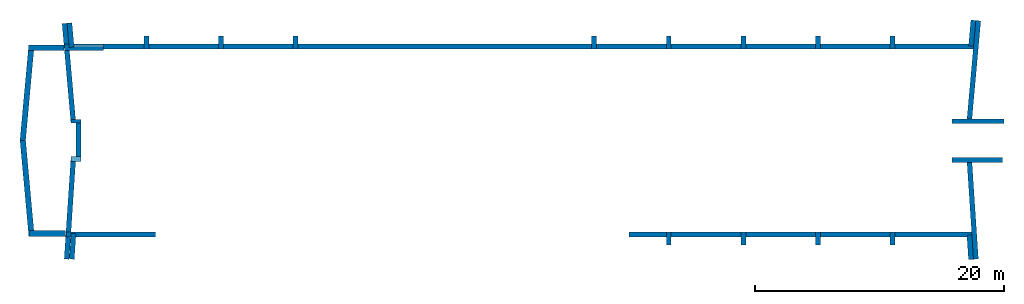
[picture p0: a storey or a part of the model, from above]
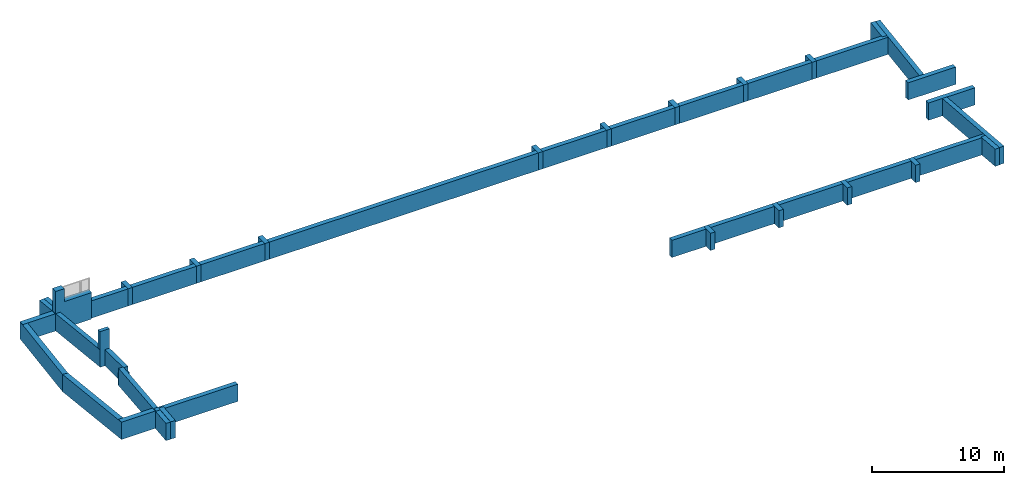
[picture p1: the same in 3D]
Properties of the parts of a building model (IFC2X3)

# File
Description: ViewDefinition [CoordinationView_V2.0], Option [Drawing Scale: 100.000000], Option [Global Unique Identifiers (GUID): Keep existing], Option [Elements to export: Visible elements (on all stories)], Option [Partial Structure Display: Entire Model], Option [IFC Domain: All], Option [Structural Function: All Elements], Option [Convert Grid elements: On], Option [Convert IFC Annotations and ArchiCAD 2D elements: Off], Option [Convert 2D symbols of Doors and Windows: Off], Option [Explode Composite and Complex Profile elements into parts: Off], Option [Export geometries that Participates in Collision Detection only: On], Option [Multi-skin complex geometries: Building element parts], Option [Elements in Solid Element Operations: Extruded/revolved], Option [Elements with junctions: Extruded/revolved without junctions], Option [Slabs with slanted edge(s): Extruded], Option [Use legacy geometric methods as in Coordination View 1.0: Off], Option [IFC Site Geometry: As boundary representation (BRep)], Option [Properties To Export: All properties], Option [Space containment: Off], Option [Bounding Box: Off], Option [Geometry to type objects: Off], Option [IFC base quantities (size, area and volume): Off], Option [All ArchiCAD BIM parameters: Off], Option [IFC Space boundaries: Off], Option [ArchiCAD Zone Categories as IFC Space classification data: Off]
File name: E:\My Documents\AAJOO2108\LasnamĆ¤e mehaanikakool\UUS PROJEKT\TĆ–Ć–\TLMK AR PP TP, SA koos\MUDEL\AR_TLMK_PP_15.02.19.ifc
Time: 2019-02-15T14:08:49
Author: Architect
Organization: Building Designer Office
Written by: PreProc - EDM 5.0
Made in: IFC file generated by Graphisoft ArchiCAD-64 19.0.0 INT FULL Windows version (IFC2x3 add-on version: 3003 INT FULL).
Authorization: The authorising person

# IfcSite, Site
RefLatitude: 24, 28, 0, 0; RefLongitude: 54, 25, 0, 0; RefElevation: 0 mm

# IfcBuildingStorey (6)
In: Building
Name | Elevation (mm)
Sokkel | -5000
1KORRUS | -3400
2KORRUS | 0
3KORRUS | 3200
4KORRUS | 6300
5KORRUS | 9500

# IfcSpace: Office (261)
InteriorOrExteriorSpace: INTERNAL
Pset_SpaceCommon - Category: Office
AC_Pset_RenovationAndPhasing - Renovation Status: Existing
Name | In
104 | 1KORRUS
101 | 1KORRUS | LongName: FUAJEE
105 | 1KORRUS
103 | 1KORRUS
102 | 1KORRUS | LongName: VALVE
333 | 3KORRUS
366 | 3KORRUS
341 | 3KORRUS
358 | 3KORRUS
306 | 3KORRUS
337 | 3KORRUS
334 | 3KORRUS
343 | 3KORRUS
347 | 3KORRUS
375 | 3KORRUS
317 | 3KORRUS
380 | 3KORRUS
335 | 3KORRUS
383 | 3KORRUS
303 | 3KORRUS
331 | 3KORRUS
305a | 3KORRUS
336 | 3KORRUS
338 | 3KORRUS
339 | 3KORRUS
340 | 3KORRUS
308 | 3KORRUS
362 | 3KORRUS
361 | 3KORRUS
369 | 3KORRUS
332 | 3KORRUS
368 | 3KORRUS
355 | 3KORRUS
357 | 3KORRUS
356 | 3KORRUS
354 | 3KORRUS
360 | 3KORRUS
363 | 3KORRUS
364 | 3KORRUS
365 | 3KORRUS
382 | 3KORRUS
378 | 3KORRUS
381 | 3KORRUS
350 | 3KORRUS
379 | 3KORRUS
349 | 3KORRUS
353 | 3KORRUS
352 | 3KORRUS
351 | 3KORRUS
376 | 3KORRUS
348 | 3KORRUS
373 | 3KORRUS
374 | 3KORRUS
372 | 3KORRUS
316 | 3KORRUS
311 | 3KORRUS
310 | 3KORRUS
309 | 3KORRUS
305 | 3KORRUS
377 | 3KORRUS
370 | 3KORRUS
371 | 3KORRUS
359 | 3KORRUS
325 | 3KORRUS
330 | 3KORRUS
328 | 3KORRUS
329 | 3KORRUS
326 | 3KORRUS
315 | 3KORRUS
314 | 3KORRUS
313 | 3KORRUS
312 | 3KORRUS
307 | 3KORRUS
302 | 3KORRUS
304 | 3KORRUS
301 | 3KORRUS
344 | 3KORRUS
342 | 3KORRUS
346 | 3KORRUS
345 | 3KORRUS
319 | 3KORRUS
318 | 3KORRUS
323 | 3KORRUS
322 | 3KORRUS
321 | 3KORRUS
320 | 3KORRUS
324 | 3KORRUS
318a | 3KORRUS
424 | 4KORRUS
402 | 4KORRUS
460 | 4KORRUS
467 | 4KORRUS
2 x 459 | 4KORRUS
415 | 4KORRUS
465 | 4KORRUS
418 | 4KORRUS
426 | 4KORRUS
471 | 4KORRUS
309 | 4KORRUS
474 | 4KORRUS
478 | 4KORRUS
439 | 4KORRUS
455 | 4KORRUS
2 x 433 | 4KORRUS
464 | 4KORRUS
420 | 4KORRUS
457 | 4KORRUS
418a | 4KORRUS
438 | 4KORRUS
440 | 4KORRUS
437 | 4KORRUS
412 | 4KORRUS
414 | 4KORRUS
425 | 4KORRUS
405 | 4KORRUS
404 | 4KORRUS
427 | 4KORRUS
422 | 4KORRUS
410 | 4KORRUS
411 | 4KORRUS
458 | 4KORRUS
423 | 4KORRUS
486 | 4KORRUS
485 | 4KORRUS
484 | 4KORRUS
487 | 4KORRUS
450 | 4KORRUS
401 | 4KORRUS
444 | 4KORRUS
462 | 4KORRUS
483 | 4KORRUS
482 | 4KORRUS
472 | 4KORRUS
406 | 4KORRUS
466 | 4KORRUS
481 | 4KORRUS
463 | 4KORRUS
479 | 4KORRUS
476 | 4KORRUS
416 | 4KORRUS
317 | 4KORRUS
477 | 4KORRUS
429 | 4KORRUS
430 | 4KORRUS
469 | 4KORRUS
470 | 4KORRUS
473 | 4KORRUS
419 | 4KORRUS
413 | 4KORRUS
431 | 4KORRUS
448 | 4KORRUS
447 | 4KORRUS
454 | 4KORRUS
428 | 4KORRUS
432 | 4KORRUS
435 | 4KORRUS
434 | 4KORRUS
436 | 4KORRUS
441 | 4KORRUS
443 | 4KORRUS
453 | 4KORRUS
452 | 4KORRUS
445 | 4KORRUS
446 | 4KORRUS
451 | 4KORRUS
456 | 4KORRUS
407 | 4KORRUS
403 | 4KORRUS
421 | 4KORRUS
480 | 4KORRUS
408 | 4KORRUS
402a | 4KORRUS
525 | 5KORRUS
526 | 5KORRUS
552 | 5KORRUS
564 | 5KORRUS
543 | 5KORRUS
544 | 5KORRUS
541 | 5KORRUS
563 | 5KORRUS
530 | 5KORRUS
558 | 5KORRUS
584 | 5KORRUS
582 | 5KORRUS
532 | 5KORRUS
583 | 5KORRUS
562 | 5KORRUS
570 | 5KORRUS
560 | 5KORRUS
540 | 5KORRUS
561 | 5KORRUS
535 | 5KORRUS
539 | 5KORRUS
529 | 5KORRUS
545 | 5KORRUS
542 | 5KORRUS
549 | 5KORRUS
556 | 5KORRUS
559 | 5KORRUS
533 | 5KORRUS
551 | 5KORRUS
527 | 5KORRUS
528 | 5KORRUS
524 | 5KORRUS
511 | 5KORRUS
509 | 5KORRUS
508 | 5KORRUS
573 | 5KORRUS
575 | 5KORRUS
550 | 5KORRUS
574 | 5KORRUS
569 | 5KORRUS
548 | 5KORRUS
571 | 5KORRUS
572 | 5KORRUS
555 | 5KORRUS
557 | 5KORRUS
534 | 5KORRUS
536 | 5KORRUS
546 | 5KORRUS
538 | 5KORRUS
537 | 5KORRUS
547 | 5KORRUS
531 | 5KORRUS
502a | 5KORRUS
504 | 5KORRUS
503 | 5KORRUS
512 | 5KORRUS
513 | 5KORRUS
510 | 5KORRUS
553 | 5KORRUS
554 | 5KORRUS
501 | 5KORRUS
585 | 5KORRUS
581 | 5KORRUS
502 | 5KORRUS
576 | 5KORRUS
577 | 5KORRUS
578 | 5KORRUS
567 | 5KORRUS
565 | 5KORRUS
568 | 5KORRUS
566 | 5KORRUS
580 | 5KORRUS
579 | 5KORRUS
505 | 5KORRUS
506 | 5KORRUS
507 | 5KORRUS
514 | 5KORRUS
515 | 5KORRUS
516 | 5KORRUS
517 | 5KORRUS
518 | 5KORRUS
2 x 518a | 5KORRUS
520 | 5KORRUS
521 | 5KORRUS
522 | 5KORRUS
523 | 5KORRUS

# IfcBuildingElementProxy: Vertical Ladder 19, R1
In: 5KORRUS
Description: REDEL; Material: Background
AC_Pset_RenovationAndPhasing - Renovation Status: Existing

# IfcBuildingElementProxy: Wheelchair Man Symbol 19 (4)
In: 3KORRUS
Material: Background
AC_Pset_RenovationAndPhasing - Renovation Status: Existing

# IfcCovering: Alumiiniumprofiil 50 (61)
Description: Ripplagi; PredefinedType: CEILING; Material: Alumiiniumprofiil
Pset_CoveringCommon - Material: Alumiiniumprofiil
AC_Pset_RenovationAndPhasing - Renovation Status: Existing
Name | In
RL2 | 1KORRUS
18 x RL2 | 3KORRUS
RL3 | 3KORRUS
21 x RL2 | 4KORRUS
19 x RL2 | 5KORRUS
RL3 | 5KORRUS

# IfcCovering: Betoon 50 (5)
Description: Ripplagi; PredefinedType: CEILING; Material: Betoon
Pset_CoveringCommon - Material: Betoon
AC_Pset_RenovationAndPhasing - Renovation Status: Existing
Name | In
3 x RL1 | 1KORRUS
2 x RL2 | 5KORRUS

# IfcCovering: Terasvõrk 50 (9)
Description: Ripplagi; PredefinedType: CEILING; Material: Terasvõrk
Pset_CoveringCommon - Material: Terasvõrk
AC_Pset_RenovationAndPhasing - Renovation Status: Existing
Name | In
RL1 | 3KORRUS
2 x RL3 | 3KORRUS
RL1 | 4KORRUS
2 x RL3 | 4KORRUS
2 x RL3 | 5KORRUS
RL1 | 5KORRUS

# IfcCovering: UmbKipsplaat 50 (75)
Description: Ripplagi; PredefinedType: CEILING; Material: UmbKipsplaat
Pset_CoveringCommon - Material: UmbKipsplaat
AC_Pset_RenovationAndPhasing - Renovation Status: Existing
Name | In
RL7 | 3KORRUS
24 x RL1 | 3KORRUS
25 x RL1 | 4KORRUS
25 x RL1 | 5KORRUS

# IfcCovering: Window 19 (3)
Description: VENT.REST; Material: Background
Pset_CoveringCommon - Material: Background
AC_Pset_RenovationAndPhasing - Renovation Status: New
Name | In
VR1 | 3KORRUS
VR1 | 4KORRUS
VR1 | 5KORRUS

# IfcDoor: Door 19 (3)
Type - OperationType: SINGLE_SWING_LEFT; ParameterTakesPrecedence: no; Sizeable: no
Type - Door Lining Properties - LiningDepth: 115 mm; LiningThickness: 40 mm; LiningOffset: -185 mm
Type - Door Panel Properties - Panel 1 - PanelDepth: 40 mm; PanelOperation: SWINGING; PanelWidth: 1; PanelPosition: MIDDLE
Description: Tamme spoon, must peits; OverallHeight: 2100 mm; OverallWidth: 900 mm; Material: Background
AC_Pset_RenovationAndPhasing - Renovation Status: New
Name | In
SU2-6 | 3KORRUS
SU2-6 | 4KORRUS
SU2-6 | 5KORRUS

# IfcDoor: Door 19, SU2-6
In: 3KORRUS
Type - OperationType: SINGLE_SWING_LEFT; ParameterTakesPrecedence: no; Sizeable: no
Type - Door Lining Properties - LiningDepth: 115 mm; LiningThickness: 40 mm; LiningOffset: -3.33067e-13 mm
Type - Door Panel Properties - Panel 1 - PanelDepth: 40 mm; PanelOperation: SWINGING; PanelWidth: 1; PanelPosition: MIDDLE
Description: Tamme spoon, must peits; OverallHeight: 2100 mm; OverallWidth: 900 mm; Material: Background
AC_Pset_RenovationAndPhasing - Renovation Status: New

# IfcDoor: Door 19 (40)
Type - OperationType: SINGLE_SWING_LEFT; ParameterTakesPrecedence: no; Sizeable: no
Type - Door Lining Properties - LiningDepth: 115 mm; LiningThickness: 40 mm; LiningOffset: -35 mm
Type - Door Panel Properties - Panel 1 - PanelDepth: 40 mm; PanelOperation: SWINGING; PanelWidth: 1; PanelPosition: MIDDLE
OverallHeight: 2100 mm; Material: Background
AC_Pset_RenovationAndPhasing - Renovation Status: New
Name | In | Description | OverallWidth (mm)
7 x SU3-5 | 3KORRUS | RAL9016 | 800
SU2-6 | 3KORRUS | Tamme spoon, must peits | 900
SU2-3 | 3KORRUS | Tamme spoon, must peits | 900
9 x SU3-5 | 4KORRUS | RAL9016 | 800
SU2-3 | 4KORRUS | Tamme spoon, must peits | 900
SU2-4 | 4KORRUS | Tamme spoon, must peits | 900
14 x SU3-5 | 5KORRUS | RAL9016 | 800
2 x SU2-3 | 5KORRUS | Tamme spoon, must peits | 900
SU2-4 | 5KORRUS | Tamme spoon, must peits | 900
3 x SU2-6 | 5KORRUS | Tamme spoon, must peits | 900

# IfcDoor: Door 19 (2)
Type - OperationType: SINGLE_SWING_LEFT; ParameterTakesPrecedence: no; Sizeable: no
Type - Door Lining Properties - LiningDepth: 115 mm; LiningThickness: 40 mm; LiningOffset: -7.21645e-13 mm
Type - Door Panel Properties - Panel 1 - PanelDepth: 40 mm; PanelOperation: SWINGING; PanelWidth: 1; PanelPosition: MIDDLE
Description: Tamme spoon, must peits; OverallHeight: 2100 mm; OverallWidth: 900 mm; Material: Background
AC_Pset_RenovationAndPhasing - Renovation Status: New
Name | In
SU2-6 | 4KORRUS
SU2-6 | 5KORRUS

# IfcDoor: Door 19 (82)
Type - OperationType: SINGLE_SWING_LEFT; ParameterTakesPrecedence: no; Sizeable: no
Type - Door Lining Properties - LiningDepth: 115 mm; LiningThickness: 40 mm; LiningOffset: 0 mm
Type - Door Panel Properties - Panel 1 - PanelDepth: 40 mm; PanelOperation: SWINGING; PanelWidth: 1; PanelPosition: MIDDLE
OverallHeight: 2100 mm; Material: Background
AC_Pset_RenovationAndPhasing - Renovation Status: New
Name | In | Description | OverallWidth (mm)
12 x SU3-3 | 3KORRUS | RAL9016 | 800
11 x SU2-6 | 3KORRUS | Tamme spoon, must peits | 900
2 x SU2-4 | 3KORRUS | Tamme spoon, must peits | 900
SU1-4 | 3KORRUS | RAL9016 | 1000
SU1-3 | 3KORRUS | Tamme spoon, must peits | 1000
2 x SU2-4 | 4KORRUS | Tamme spoon, must peits | 900
13 x SU3-3 | 4KORRUS | RAL9016 | 800
13 x SU2-6 | 4KORRUS | Tamme spoon, must peits | 900
SU3-5 | 4KORRUS | RAL9016 | 800
2 x SU3-5 | 5KORRUS | RAL9016 | 800
12 x SU3-3 | 5KORRUS | RAL9016 | 800
10 x SU2-6 | 5KORRUS | Tamme spoon, must peits | 900
2 x SU2-4 | 5KORRUS | Tamme spoon, must peits | 900

# IfcDoor: Door 19 (2)
In: 1KORRUS
Type - OperationType: SINGLE_SWING_LEFT; ParameterTakesPrecedence: no; Sizeable: no
Type - Door Lining Properties - LiningDepth: 115 mm; LiningThickness: 40 mm; LiningOffset: 200 mm
Type - Door Panel Properties - Panel 1 - PanelDepth: 40 mm; PanelOperation: SWINGING; PanelWidth: 1; PanelPosition: MIDDLE
OverallHeight: 2100 mm; OverallWidth: 1000 mm; Material: Background
AC_Pset_RenovationAndPhasing - Renovation Status: Existing

# IfcDoor: Door 19 (16)
Type - OperationType: SINGLE_SWING_LEFT; ParameterTakesPrecedence: no; Sizeable: no
Type - Door Lining Properties - LiningDepth: 115 mm; LiningThickness: 40 mm; LiningOffset: 265 mm
Type - Door Panel Properties - Panel 1 - PanelDepth: 40 mm; PanelOperation: SWINGING; PanelWidth: 1; PanelPosition: MIDDLE
Description: RAL9016; OverallHeight: 2100 mm; OverallWidth: 800 mm; Material: Background
AC_Pset_RenovationAndPhasing - Renovation Status: New
Name | In
5 x SU3-5 | 3KORRUS
SU3-1 | 3KORRUS
6 x SU3-5 | 4KORRUS
4 x SU3-5 | 5KORRUS

# IfcDoor: Door 19 (3)
Type - OperationType: SINGLE_SWING_LEFT; ParameterTakesPrecedence: no; Sizeable: no
Type - Door Lining Properties - LiningDepth: 115 mm; LiningThickness: 40 mm; LiningOffset: 300 mm
Type - Door Panel Properties - Panel 1 - PanelDepth: 40 mm; PanelOperation: SWINGING; PanelWidth: 1; PanelPosition: MIDDLE
OverallHeight: 2100 mm; Material: Background
AC_Pset_RenovationAndPhasing - Renovation Status: New
Name | In | Description | OverallWidth (mm)
SU3-1 | 3KORRUS | RAL9016 | 800
SU2-6 | 4KORRUS | Tamme spoon, must peits | 900
SU2-6 | 5KORRUS | Tamme spoon, must peits | 900

# IfcDoor: Door 19 (2)
In: 1KORRUS
Type - OperationType: SINGLE_SWING_LEFT; ParameterTakesPrecedence: no; Sizeable: no
Type - Door Lining Properties - LiningDepth: 115 mm; LiningThickness: 40 mm; LiningOffset: 600 mm
Type - Door Panel Properties - Panel 1 - PanelDepth: 40 mm; PanelOperation: SWINGING; PanelWidth: 1; PanelPosition: MIDDLE
OverallHeight: 2100 mm; OverallWidth: 1000 mm; Material: Background
AC_Pset_RenovationAndPhasing - Renovation Status: Existing

# IfcDoor: Door 19 (14)
Type - OperationType: SINGLE_SWING_RIGHT; ParameterTakesPrecedence: no; Sizeable: no
Type - Door Lining Properties - LiningDepth: 115 mm; LiningThickness: 40 mm; LiningOffset: -3.33067e-13 mm
Type - Door Panel Properties - Panel 1 - PanelDepth: 40 mm; PanelOperation: SWINGING; PanelWidth: 1; PanelPosition: MIDDLE
OverallHeight: 2100 mm; Material: Background
AC_Pset_RenovationAndPhasing - Renovation Status: New
Name | In | Description | OverallWidth (mm)
2 x SU2-5 | 3KORRUS | Tamme spoon, must peits | 900
SU2-1 | 3KORRUS | Tamme spoon, must peits | 900
SU1-1 | 3KORRUS | Tamme spoon, must peits | 1000
SU1-2 | 3KORRUS | RAL9016 | 1000
3 x SU2-5 | 4KORRUS | Tamme spoon, must peits | 900
SU3-2 | 4KORRUS | RAL9016 | 800
2 x SU3-2 | 5KORRUS | RAL9016 | 800
3 x SU2-5 | 5KORRUS | Tamme spoon, must peits | 900

# IfcDoor: Door 19 (25)
Type - OperationType: SINGLE_SWING_RIGHT; ParameterTakesPrecedence: no; Sizeable: no
Type - Door Lining Properties - LiningDepth: 115 mm; LiningThickness: 40 mm; LiningOffset: -35 mm
Type - Door Panel Properties - Panel 1 - PanelDepth: 40 mm; PanelOperation: SWINGING; PanelWidth: 1; PanelPosition: MIDDLE
OverallHeight: 2100 mm; Material: Background
AC_Pset_RenovationAndPhasing - Renovation Status: New
Name | In | Description | OverallWidth (mm)
7 x SU3-4 | 3KORRUS | RAL9016 | 800
SU2-1 | 4KORRUS | Tamme spoon, must peits | 900
9 x SU3-4 | 4KORRUS | RAL9016 | 800
8 x SU3-4 | 5KORRUS | RAL9016 | 800

# IfcDoor: Door 19 (5)
Type - OperationType: SINGLE_SWING_RIGHT; ParameterTakesPrecedence: no; Sizeable: no
Type - Door Lining Properties - LiningDepth: 115 mm; LiningThickness: 40 mm; LiningOffset: 0 mm; CasingThickness: 50 mm; CasingDepth: 19 mm
Type - Door Panel Properties - Panel 1 - PanelDepth: 40 mm; PanelOperation: SWINGING; PanelWidth: 1; PanelPosition: MIDDLE
Description: metall, klaas; OverallHeight: 2100 mm; OverallWidth: 900 mm; Material: Background
AC_Pset_RenovationAndPhasing - Renovation Status: New
Name | In
Liftiuks | 1KORRUS
Liftiuks | 2KORRUS
Liftiuks | 3KORRUS
Liftiuks | 4KORRUS
Liftiuks | 5KORRUS

# IfcDoor: Door 19 (13)
Type - OperationType: SINGLE_SWING_RIGHT; ParameterTakesPrecedence: no; Sizeable: no
Type - Door Lining Properties - LiningDepth: 115 mm; LiningThickness: 40 mm; LiningOffset: 0 mm
Type - Door Panel Properties - Panel 1 - PanelDepth: 40 mm; PanelOperation: SWINGING; PanelWidth: 1; PanelPosition: MIDDLE
OverallHeight: 2100 mm; Material: Background
AC_Pset_RenovationAndPhasing - Renovation Status: New
Name | In | Description | OverallWidth (mm)
SU3-2 | 1KORRUS | RAL9016 | 800
2 x SU2-2 | 3KORRUS | RAL9016 | 900
2 x SU2-5 | 3KORRUS | Tamme spoon, must peits | 900
SU3-4 | 3KORRUS | RAL9016 | 800
SU3-4 | 4KORRUS | RAL9016 | 800
SU2-5 | 4KORRUS | Tamme spoon, must peits | 900
SU2-2 | 4KORRUS | RAL9016 | 900
SU2-5 | 5KORRUS | Tamme spoon, must peits | 900
2 x SU3-4 | 5KORRUS | RAL9016 | 800
SU2-2 | 5KORRUS | RAL9016 | 900

# IfcDoor: Door 19 (14)
Type - OperationType: SINGLE_SWING_RIGHT; ParameterTakesPrecedence: no; Sizeable: no
Type - Door Lining Properties - LiningDepth: 115 mm; LiningThickness: 40 mm; LiningOffset: 1.44329e-12 mm
Type - Door Panel Properties - Panel 1 - PanelDepth: 40 mm; PanelOperation: SWINGING; PanelWidth: 1; PanelPosition: MIDDLE
Description: RAL9016; OverallHeight: 2100 mm; OverallWidth: 800 mm; Material: Background
AC_Pset_RenovationAndPhasing - Renovation Status: New
Name | In
5 x SU3-2 | 3KORRUS
5 x SU3-2 | 4KORRUS
4 x SU3-2 | 5KORRUS

# IfcDoor: Door 19 (2)
In: 1KORRUS
Type - OperationType: SINGLE_SWING_RIGHT; ParameterTakesPrecedence: no; Sizeable: no
Type - Door Lining Properties - LiningDepth: 115 mm; LiningThickness: 40 mm; LiningOffset: 200 mm
Type - Door Panel Properties - Panel 1 - PanelDepth: 40 mm; PanelOperation: SWINGING; PanelWidth: 1; PanelPosition: MIDDLE
OverallHeight: 2100 mm; OverallWidth: 1000 mm; Material: Background
AC_Pset_RenovationAndPhasing - Renovation Status: Existing

# IfcDoor: Door 19 (23)
Type - OperationType: SINGLE_SWING_RIGHT; ParameterTakesPrecedence: no; Sizeable: no
Type - Door Lining Properties - LiningDepth: 115 mm; LiningThickness: 40 mm; LiningOffset: 265 mm
Type - Door Panel Properties - Panel 1 - PanelDepth: 40 mm; PanelOperation: SWINGING; PanelWidth: 1; PanelPosition: MIDDLE
Description: RAL9016; OverallHeight: 2100 mm; OverallWidth: 800 mm; Material: Background
AC_Pset_RenovationAndPhasing - Renovation Status: New
Name | In
7 x SU3-4 | 3KORRUS
SU3-5 | 3KORRUS
8 x SU3-4 | 4KORRUS
SU3-5 | 4KORRUS
4 x SU3-4 | 5KORRUS
SU3-2 | 5KORRUS
SU3-5 | 5KORRUS

# IfcDoor: Door 19 (2)
Type - OperationType: SINGLE_SWING_RIGHT; ParameterTakesPrecedence: no; Sizeable: no
Type - Door Lining Properties - LiningDepth: 115 mm; LiningThickness: 40 mm; LiningOffset: 300 mm
Type - Door Panel Properties - Panel 1 - PanelDepth: 40 mm; PanelOperation: SWINGING; PanelWidth: 1; PanelPosition: MIDDLE
Description: Tamme spoon, must peits; OverallHeight: 2100 mm; OverallWidth: 900 mm; Material: Background
AC_Pset_RenovationAndPhasing - Renovation Status: New
Name | In
SU2-5 | 4KORRUS
SU2-5 | 5KORRUS

# IfcDoor: Door 19 (2)
Type - OperationType: SINGLE_SWING_RIGHT; ParameterTakesPrecedence: no; Sizeable: no
Type - Door Lining Properties - LiningDepth: 115 mm; LiningThickness: 40 mm; LiningOffset: 600 mm
Type - Door Panel Properties - Panel 1 - PanelDepth: 40 mm; PanelOperation: SWINGING; PanelWidth: 1; PanelPosition: MIDDLE
OverallHeight: 2100 mm; Material: Background
AC_Pset_RenovationAndPhasing - Renovation Status: Existing
Name | In | OverallWidth (mm)
ava | 1KORRUS | 700
KLA | 2KORRUS | 800

# IfcDoor: Door 19 (2)
In: 1KORRUS
Type - OperationType: SINGLE_SWING_RIGHT; ParameterTakesPrecedence: no; Sizeable: no
Type - Door Lining Properties - LiningDepth: 115 mm; LiningThickness: 40 mm; LiningOffset: 800 mm
Type - Door Panel Properties - Panel 1 - PanelDepth: 40 mm; PanelOperation: SWINGING; PanelWidth: 1; PanelPosition: MIDDLE
OverallHeight: 2100 mm; Material: Background
AC_Pset_RenovationAndPhasing - Renovation Status: New
Name | Description | OverallWidth (mm)
SU7 | RAL9005, kirgas klaas | 900
VU1 | ALUMIINIUMRAAMIS KLAASUKS | 1000

# IfcDoor: Double Door 19 (4)
Type - OperationType: DOUBLE_DOOR_SINGLE_SWING; ParameterTakesPrecedence: no; Sizeable: no
Type - Door Lining Properties - LiningDepth: 115 mm; LiningThickness: 40 mm; LiningOffset: 315 mm; CasingThickness: 50 mm; CasingDepth: 19 mm
Type - Door Panel Properties - Panel 1 - PanelDepth: 40 mm; PanelOperation: SWINGING; PanelWidth: 0.506977; PanelPosition: LEFT
Type - Door Panel Properties - Panel 2 - PanelDepth: 40 mm; PanelOperation: SWINGING; PanelWidth: 0.506977; PanelPosition: RIGHT
Description: RAL9005, kirgas klaas; OverallHeight: 2100 mm; OverallWidth: 1800 mm; Material: Background
AC_Pset_RenovationAndPhasing - Renovation Status: New
Name | In
SU5 | 2KORRUS
SU5 | 3KORRUS
SU5 | 4KORRUS
SU5 | 5KORRUS

# IfcDoor: Double Door 19, ava
In: 1KORRUS
Type - OperationType: DOUBLE_DOOR_SINGLE_SWING; ParameterTakesPrecedence: no; Sizeable: no
Type - Door Lining Properties - LiningDepth: 115 mm; LiningThickness: 40 mm; LiningOffset: 600 mm
Type - Door Panel Properties - Panel 1 - PanelDepth: 40 mm; PanelOperation: SWINGING; PanelWidth: 0.508451; PanelPosition: LEFT
Type - Door Panel Properties - Panel 2 - PanelDepth: 40 mm; PanelOperation: SWINGING; PanelWidth: 0.508451; PanelPosition: RIGHT
OverallHeight: 2100 mm; OverallWidth: 1500 mm; Material: Background
AC_Pset_RenovationAndPhasing - Renovation Status: Existing

# IfcDoor: Double Door 19, A4
In: 4KORRUS
Type - OperationType: DOUBLE_DOOR_SINGLE_SWING; ParameterTakesPrecedence: no; Sizeable: no
Type - Door Lining Properties - LiningDepth: 115 mm; LiningThickness: 40 mm; LiningOffset: 715 mm
Type - Door Panel Properties - Panel 1 - PanelDepth: 40 mm; PanelOperation: SWINGING; PanelWidth: 0.508451; PanelPosition: LEFT
Type - Door Panel Properties - Panel 2 - PanelDepth: 40 mm; PanelOperation: SWINGING; PanelWidth: 0.508451; PanelPosition: RIGHT
Description: METALLUKS; OverallHeight: 2100 mm; OverallWidth: 1500 mm; Material: Background
AC_Pset_RenovationAndPhasing - Renovation Status: New

# IfcDoor: Double Door 19 (2)
Type - OperationType: DOUBLE_DOOR_SINGLE_SWING; ParameterTakesPrecedence: no; Sizeable: no
Type - Door Lining Properties - LiningDepth: 115 mm; LiningThickness: 40 mm; LiningOffset: 800 mm
Type - Door Panel Properties - Panel 1 - PanelDepth: 40 mm; PanelOperation: SWINGING; PanelWidth: 0.508451; PanelPosition: RIGHT
Type - Door Panel Properties - Panel 2 - PanelDepth: 40 mm; PanelOperation: SWINGING; PanelWidth: 0.508451; PanelPosition: LEFT
Description: METALLUKS; OverallHeight: 2100 mm; OverallWidth: 1500 mm; Material: Background
AC_Pset_RenovationAndPhasing - Renovation Status: New
Name | In
ava | 3KORRUS
A4 | 5KORRUS

# IfcDoor: Double Door Asymmetric 19 (3)
Type - OperationType: DOUBLE_DOOR_SINGLE_SWING; ParameterTakesPrecedence: no; Sizeable: no
Type - Door Lining Properties - LiningDepth: 115 mm; LiningThickness: 40 mm; LiningOffset: 0 mm
Type - Door Panel Properties - Panel 1 - PanelDepth: 40 mm; PanelOperation: SWINGING; PanelWidth: 0.281967; PanelPosition: LEFT
Type - Door Panel Properties - Panel 2 - PanelDepth: 40 mm; PanelOperation: SWINGING; PanelWidth: 0.737705; PanelPosition: RIGHT
Description: RAL9005, kirgas klaas; OverallHeight: 2100 mm; OverallWidth: 1300 mm; Material: Background
AC_Pset_RenovationAndPhasing - Renovation Status: Existing
Name | In
SU4-22 | 3KORRUS
SU4-22 | 4KORRUS
SU4-22 | 5KORRUS

# IfcDoor: Double Door Asymmetric 19, SU4-1
In: 1KORRUS
Type - OperationType: DOUBLE_DOOR_SINGLE_SWING; ParameterTakesPrecedence: no; Sizeable: no
Type - Door Lining Properties - LiningDepth: 115 mm; LiningThickness: 40 mm; LiningOffset: 0 mm
Type - Door Panel Properties - Panel 1 - PanelDepth: 40 mm; PanelOperation: SWINGING; PanelWidth: 0.281967; PanelPosition: RIGHT
Type - Door Panel Properties - Panel 2 - PanelDepth: 40 mm; PanelOperation: SWINGING; PanelWidth: 0.737705; PanelPosition: LEFT
Description: RAL9005, kirgas klaas; OverallHeight: 2100 mm; OverallWidth: 1300 mm; Material: Background
AC_Pset_RenovationAndPhasing - Renovation Status: New

# IfcDoor: Double Door Asymmetric 19 (3)
Type - OperationType: DOUBLE_DOOR_SINGLE_SWING; ParameterTakesPrecedence: no; Sizeable: no
Type - Door Lining Properties - LiningDepth: 115 mm; LiningThickness: 40 mm; LiningOffset: 415 mm
Type - Door Panel Properties - Panel 1 - PanelDepth: 40 mm; PanelOperation: SWINGING; PanelWidth: 0.281967; PanelPosition: LEFT
Type - Door Panel Properties - Panel 2 - PanelDepth: 40 mm; PanelOperation: SWINGING; PanelWidth: 0.737705; PanelPosition: RIGHT
Description: RAL9005, kirgas klaas; OverallHeight: 2100 mm; OverallWidth: 1300 mm; Material: Background
AC_Pset_RenovationAndPhasing - Renovation Status: Existing
Name | In
SU4-22 | 4KORRUS
2 x SU4-22 | 5KORRUS

# IfcDoor: Double Door Asymmetric 19 (7)
Type - OperationType: DOUBLE_DOOR_SINGLE_SWING; ParameterTakesPrecedence: no; Sizeable: no
Type - Door Lining Properties - LiningDepth: 115 mm; LiningThickness: 40 mm; LiningOffset: 600 mm
Type - Door Panel Properties - Panel 1 - PanelDepth: 40 mm; PanelOperation: SWINGING; PanelWidth: 0.281967; PanelPosition: LEFT
Type - Door Panel Properties - Panel 2 - PanelDepth: 40 mm; PanelOperation: SWINGING; PanelWidth: 0.737705; PanelPosition: RIGHT
Description: RAL9005, kirgas klaas; OverallHeight: 2100 mm; OverallWidth: 1300 mm; Material: Background
Name | In | Renovation Status
SU4-2 | 2KORRUS | New
2 x SU4-22 | 3KORRUS | Existing
SU4-2 | 3KORRUS | New
SU4-2 | 4KORRUS | New
SU4-22 | 4KORRUS | Existing
SU4-2 | 5KORRUS | New

# IfcDoor: Double Door with Transom 19, KLA1
In: 1KORRUS
Type - OperationType: DOUBLE_DOOR_SINGLE_SWING; ParameterTakesPrecedence: no; Sizeable: no
Type - Door Lining Properties - LiningDepth: 115 mm; LiningThickness: 40 mm; TransomThickness: 40 mm; TransomOffset: 2100 mm; LiningOffset: -150 mm
Type - Door Panel Properties - Panel 1 - PanelDepth: 40 mm; PanelOperation: SWINGING; PanelWidth: 0.506977; PanelPosition: RIGHT
Type - Door Panel Properties - Panel 2 - PanelDepth: 40 mm; PanelOperation: SWINGING; PanelWidth: 0.506977; PanelPosition: LEFT
Description: KLAASFASSAADISÜSTEEM ALUMIINIUMIST; OverallHeight: 2800 mm; OverallWidth: 1800 mm; Material: Background
AC_Pset_RenovationAndPhasing - Renovation Status: New

# IfcDoor: Exterior Sliding Door 19, SU6-2
In: 3KORRUS
Type - OperationType: SLIDING_TO_LEFT; ParameterTakesPrecedence: no; Sizeable: no
Type - Door Lining Properties - LiningDepth: 100 mm; LiningThickness: 50 mm
Type - Door Panel Properties - Panel 1 - PanelDepth: 40 mm; PanelOperation: SLIDING; PanelWidth: 1; PanelPosition: MIDDLE
Description: RAL9016, lamineeritud matt klaas; OverallHeight: 2100 mm; OverallWidth: 1600 mm; Material: Background
AC_Pset_RenovationAndPhasing - Renovation Status: New

# IfcDoor: Exterior Sliding Door 19, SU6-1
In: 3KORRUS
Type - OperationType: SLIDING_TO_RIGHT; ParameterTakesPrecedence: no; Sizeable: no
Type - Door Lining Properties - LiningDepth: 100 mm; LiningThickness: 50 mm
Type - Door Panel Properties - Panel 1 - PanelDepth: 40 mm; PanelOperation: SLIDING; PanelWidth: 1; PanelPosition: MIDDLE
Description: RAL9016, lamineeritud matt klaas; OverallHeight: 2100 mm; OverallWidth: 1600 mm; Material: Background
AC_Pset_RenovationAndPhasing - Renovation Status: New

# IfcFlowTerminal: Basin 19 (65)
Type - PredefinedType: WASHHANDBASIN
Material: Background
AC_Pset_RenovationAndPhasing - Renovation Status: Existing
Name | In
FU - 006 | 1KORRUS
22 x FU - 006 | 3KORRUS
21 x FU - 006 | 4KORRUS
21 x FU - 006 | 5KORRUS

# IfcFlowTerminal: Cabinet Base Single Door 19 (161)
Type - PredefinedType: SINK
Material: Background
AC_Pset_RenovationAndPhasing - Renovation Status: Existing
Name | In
FU - 007 | 1KORRUS
53 x FU - 007 | 3KORRUS
61 x FU - 007 | 4KORRUS
46 x FU - 007 | 5KORRUS

# IfcFlowTerminal: Shower Tray 19 (60)
Type - PredefinedType: SHOWER
Material: Background
AC_Pset_RenovationAndPhasing - Renovation Status: Existing
Name | In
FU - 005 | 1KORRUS
19 x FU - 005 | 3KORRUS
20 x FU - 005 | 4KORRUS
20 x FU - 005 | 5KORRUS

# IfcFlowTerminal: WC 19 (60)
Type - PredefinedType: WCSEAT
Material: Background
AC_Pset_RenovationAndPhasing - Renovation Status: Existing
Name | In
FU - 004 | 1KORRUS
19 x FU - 004 | 3KORRUS
20 x FU - 004 | 4KORRUS
20 x FU - 004 | 5KORRUS

# IfcFurnishingElement: Armchair 01 19 (70)
Material: Background
AC_Pset_RenovationAndPhasing - Renovation Status: Existing
Name | In
14 x FU - 009 | 3KORRUS
8 x FU - 008 | 3KORRUS
18 x FU - 009 | 4KORRUS
30 x FU - 009 | 5KORRUS

# IfcFurnishingElement: Bed 19 (200)
Material: Background
AC_Pset_RenovationAndPhasing - Renovation Status: Existing
Name | In
68 x FU - 013 | 3KORRUS
76 x FU - 013 | 4KORRUS
56 x FU - 013 | 5KORRUS

# IfcFurnishingElement: Bed Double 19 (2)
In: 5KORRUS
Material: Background
AC_Pset_RenovationAndPhasing - Renovation Status: Existing

# IfcFurnishingElement: Built-in Cooktops 19 (54)
Material: Background
AC_Pset_RenovationAndPhasing - Renovation Status: Existing
Name | In
16 x FU - 007 | 3KORRUS
19 x FU - 007 | 4KORRUS
19 x FU - 007 | 5KORRUS

# IfcFurnishingElement: Chair 10 19 (210)
Material: Background
AC_Pset_RenovationAndPhasing - Renovation Status: Existing
Name | In
64 x FU - 008 | 3KORRUS
4 x FU - 012 | 3KORRUS
76 x FU - 008 | 4KORRUS
4 x FU - 012 | 4KORRUS
58 x FU - 008 | 5KORRUS
4 x FU - 012 | 5KORRUS

# IfcFurnishingElement: Cooktops Electric 19 (5)
Material: Background
AC_Pset_RenovationAndPhasing - Renovation Status: Existing
Name | In
3 x FU - 007 | 3KORRUS
FU - 007 | 4KORRUS
FU - 007 | 5KORRUS

# IfcFurnishingElement: Cupboard 19 (193)
Material: Background
AC_Pset_RenovationAndPhasing - Renovation Status: Existing
Name | In
64 x FU - 014 | 3KORRUS
70 x FU - 014 | 4KORRUS
59 x FU - 014 | 5KORRUS

# IfcFurnishingElement: Designer Chair 13 19 (12)
In: 5KORRUS
Material: Background
AC_Pset_RenovationAndPhasing - Renovation Status: Existing
Name
6 x FU - 008
6 x FU - 009

# IfcFurnishingElement: Designer Sofa 01 19 (2)
In: 1KORRUS
Material: Background
AC_Pset_RenovationAndPhasing - Renovation Status: Existing

# IfcFurnishingElement: Designer Sofa 03 19 (10)
Material: Background
AC_Pset_RenovationAndPhasing - Renovation Status: Existing
Name | In
3 x FU - 002 | 3KORRUS
4 x FU - 002 | 4KORRUS
3 x FU - 002 | 5KORRUS

# IfcFurnishingElement: Designer Table 02 19 (3)
Description: Diivanilaud mööbliplaadist; Material: Background
AC_Pset_RenovationAndPhasing - Renovation Status: Existing
Name | In
DL1 | 1KORRUS
2 x DL1 | 4KORRUS

# IfcFurnishingElement: Desk 19 (2)
In: 1KORRUS
Description: Diivanilaud mööbliplaadist; Material: Background
AC_Pset_RenovationAndPhasing - Renovation Status: Existing

# IfcFurnishingElement: Flat Panel TV 19 (8)
Material: Background
AC_Pset_RenovationAndPhasing - Renovation Status: Existing
Name | In
2 x FU - 005 | 3KORRUS
2 x FU - 005 | 4KORRUS
3 x FU - 005 | 5KORRUS
FU - 006 | 5KORRUS

# IfcFurnishingElement: LCD Monitor 19 (3)
In: 1KORRUS
Material: Background
AC_Pset_RenovationAndPhasing - Renovation Status: Existing

# IfcFurnishingElement: Laptop 19 (202)
Material: Background
AC_Pset_RenovationAndPhasing - Renovation Status: Existing
Name | In
68 x FU - 006 | 3KORRUS
76 x FU - 006 | 4KORRUS
58 x FU - 006 | 5KORRUS

# IfcFurnishingElement: Office Chair 04 19, FU - 009
In: 1KORRUS
Material: Background
AC_Pset_RenovationAndPhasing - Renovation Status: Existing

# IfcFurnishingElement: Rectangular Table 01 19 (199)
Material: Background
AC_Pset_RenovationAndPhasing - Renovation Status: Existing
Name | In
62 x FU - 011 | 3KORRUS
72 x FU - 011 | 4KORRUS
65 x FU - 011 | 5KORRUS

# IfcFurnishingElement: Refrigerator 19 (60)
Material: Background
AC_Pset_RenovationAndPhasing - Renovation Status: Existing
Name | In
FU - 007 | 1KORRUS
19 x FU - 007 | 3KORRUS
20 x FU - 007 | 4KORRUS
20 x FU - 007 | 5KORRUS

# IfcFurnishingElement: Round Table 01 19, FU - 004
In: 3KORRUS
Material: Background
AC_Pset_RenovationAndPhasing - Renovation Status: Existing

# IfcFurnishingElement: Sofa 19 (7)
Material: Background
AC_Pset_RenovationAndPhasing - Renovation Status: Existing
Name | In
D1 | 1KORRUS | Description: DIIVANVOODI
2 x FU - 008 | 3KORRUS
FU - 008 | 4KORRUS
FU - 008 | 5KORRUS
2 x FU - 009 | 5KORRUS

# IfcRailing: Rail Solid Frame Filled 19 (4)
In: 5KORRUS
Description: PIIRE TERAS, PLAAS; Material: Background
AC_Pset_RenovationAndPhasing - Renovation Status: Existing

# IfcRailing: Railing Horizontal 19 (3)
In: 5KORRUS
Description: TERAS, VÄRV; Material: Background
AC_Pset_RenovationAndPhasing - Renovation Status: Existing
Name
2 x PIIRE OLEMASOLEV
P1

# IfcSlab: Betoon 180, SLA - 014
In: 4KORRUS
PredefinedType: FLOOR; Material: Betoon 180 mm
AC_Pset_RenovationAndPhasing - Renovation Status: Existing

# IfcSlab: Betoon 325, SLA - 014
In: 4KORRUS
PredefinedType: FLOOR; Material: Betoon 325 mm
AC_Pset_RenovationAndPhasing - Renovation Status: Existing

# IfcSlab: Betoon 400, SLA - 007
In: 2KORRUS
Type - PredefinedType: FLOOR
Material: Betoon 400 mm
AC_Pset_RenovationAndPhasing - Renovation Status: Existing

# IfcSlab: Betoon 500, SLA - 013
In: 4KORRUS
PredefinedType: FLOOR; Material: Betoon 500 mm
AC_Pset_RenovationAndPhasing - Renovation Status: Existing

# IfcSlab: Betoon 600 (2)
In: 1KORRUS
Type - PredefinedType: FLOOR
Material: Betoon 600 mm
AC_Pset_RenovationAndPhasing - Renovation Status: Existing

# IfcSlab: Flat Roof 680, K1
In: 5KORRUS
Description: SBS kattega olev katus; PredefinedType: ROOF; Material: Sillutis, Pinnas 30 mm, Membrane - Rainproof (1) 5 mm, Vahtpolüstüreen 300 mm, Membrane - Vapor Barrier 5 mm, Reinforced Concrete - Structural (1) 320 mm, Plaster - Gypsum (1) 20 mm
AC_Pset_RenovationAndPhasing - Renovation Status: Existing

# IfcSlab: Flat Roof 680, K1
In: 3KORRUS
Type - PredefinedType: ROOF
Description: OLEV KATUS; Material: Sillutis, Pinnas 30 mm, Membrane - Rainproof (1) 5 mm, Vahtpolüstüreen 300 mm, Membrane - Vapor Barrier 5 mm, Reinforced Concrete - Structural (1) 320 mm, Plaster - Gypsum (1) 20 mm
AC_Pset_RenovationAndPhasing - Renovation Status: Existing

# IfcSlab: Generic Slab/Roof 500, K2
In: 1KORRUS
Type - PredefinedType: FLOOR
Material: GENERIC - INTERNAL CLADDING 50 mm, GENERIC - INTERNAL CLADDING 100 mm, GENERIC - STRUCTURAL (1) 350 mm
AC_Pset_RenovationAndPhasing - Renovation Status: Existing

# IfcSlab: Olemasolev põrand, vahelagi, uus viimistlus 365 (6)
PredefinedType: FLOOR; Material: Plaat 10 mm, Betoonvalu 15 mm, Vahtpolüstüreen 30 mm, Reinforced Concrete - Structural (1) 265 mm, Kile 45 mm
AC_Pset_RenovationAndPhasing - Renovation Status: Existing
Name | In | Description
P2 | 1KORRUS | OLEMASOLEV PORAND
P3 | 2KORRUS | BETOON, VIIMISTLUS
SLA - 012 | 3KORRUS | BETOON, VIIMISTLUS
P3 | 3KORRUS | BETOON, VIIMISTLUS
P3 | 4KORRUS | BETOON, VIIMISTLUS
P3 | 5KORRUS | BETOON, VIIMISTLUS

# IfcSlab: Sillutis, Pinnas 200, SILLUTIS
In: 1KORRUS
PredefinedType: FLOOR; Material: Sillutis, Pinnas 200 mm
AC_Pset_RenovationAndPhasing - Renovation Status: Existing

# IfcSlab: Teras 200, R1
In: 4KORRUS
Description: RAJATAV EVAKUATSIOONIRÕDU; PredefinedType: FLOOR; Material: Teras 200 mm
AC_Pset_RenovationAndPhasing - Renovation Status: Existing

# IfcSlab: Uus põrand betoonalusel klinkerplaat 372, P1
In: 1KORRUS
PredefinedType: FLOOR; Material: Plaat 20 mm, Betoonvalu 100 mm, Vahtpolüstüreen 250 mm, Kile 2 mm
AC_Pset_RenovationAndPhasing - Renovation Status: Existing

# IfcStair: TR1 (4)
ShapeType: TWO_STRAIGHT_RUN_STAIR; Material: 50 %
AC_Pset_RenovationAndPhasing - Renovation Status: Existing
Name | In | Description
TR1 | 1KORRUS | OLEMASOLEV BETOONTREPP UUS VIIMISTLUS KER PLAAT
TR1 | 2KORRUS | OLEMASOLEV BETOONTREPP UUS VIIMISTLUS KER PLAAT
TR1 | 3KORRUS | OLEMASOLEV BETOONTREPP UUS VIIMISTLUS KER.PLAAT
TR1 | 4KORRUS | OLEMASOLEV BETOONTREPP UUS VIIMISTLUS KER PLAAT

# IfcStair: TRE3 (4)
Material: 25 %
AC_Pset_RenovationAndPhasing - Renovation Status: Existing
Name | In | Description
TRE3 | 1KORRUS | OLEMASOLEV TREPP, UUS VIIMISTLUS KER PLAAT
TRE3 | 2KORRUS | OLEMASOLEV TREPP, UUS VIIMISTLUS KER. PLAAT
TRE3 | 3KORRUS | OLEMASOLEV TREPP UUS VIIMITLUS KER. PLAAT
TRE3 | 4KORRUS | OLEMASOLEV TREPP UUS VIIMISTLUS KER. PLAAT

# IfcWallStandardCase: Betoonvalu 450 (4)
In: Sokkel
Material: Betoonvalu 450 mm
AC_Pset_RenovationAndPhasing - Renovation Status: Existing

# IfcWallStandardCase: GENERIC - EXTERNAL CLADDING 200, SS1
In: 1KORRUS
Description: KIPSPLAATSEIN; Material: GENERIC - EXTERNAL CLADDING 200 mm
AC_Pset_RenovationAndPhasing - Renovation Status: Existing

# IfcWallStandardCase: Kergplokk Bauroc 100 100 (230)
Name | In | Description | Material | Renovation Status
4 x SS1 | 1KORRUS | KIPSPLAATSEIN | krohv 2 mm, krohv 10 mm, Kergplokk 76 mm, krohv 10 mm, krohv 2 mm | New
SS2 | 1KORRUS | KERGPLOKKSEIN EI60 | krohv 2 mm, krohv 10 mm, Kergplokk 76 mm, krohv 10 mm, krohv 2 mm | New
SS2 | 1KORRUS | KERGPLOKKSEIN EI60 | krohv 2 mm, krohv 10 mm, Kergplokk 76 mm, krohv 10 mm, krohv 2 mm | Existing
72 x SS2 | 3KORRUS | KERGPLOKKSEIN EI60 | krohv 2 mm, krohv 10 mm, Kergplokk 76 mm, krohv 10 mm, krohv 2 mm | New
SS2 | 3KORRUS | Kergplokksein EI 60 | krohv 2 mm, krohv 10 mm, Kergplokk 76 mm, krohv 10 mm, krohv 2 mm | New
2 x SS1 | 3KORRUS | KERGPLOKKSEIN EI60 | krohv 2 mm, krohv 10 mm, Kergplokk 76 mm, krohv 10 mm, krohv 2 mm | New
SS2 | 3KORRUS |  | krohv 2 mm, krohv 10 mm, Kergplokk 76 mm, krohv 10 mm, krohv 2 mm | New
2 x SS2 | 4KORRUS | KERGPLOKKSEIN EI60 | krohv 2 mm, krohv 10 mm, Kergplokk 76 mm, krohv 10 mm, krohv 2 mm | New
73 x SS2 | 4KORRUS | Kergplokksein EI 60 | krohv 2 mm, krohv 10 mm, Kergplokk 76 mm, krohv 10 mm, krohv 2 mm | New
2 x SS1 | 4KORRUS | Kipsplaatvahesein | krohv 2 mm, krohv 10 mm, Kergplokk 76 mm, krohv 10 mm, krohv 2 mm | Existing
62 x SS2 | 5KORRUS | Kergplokksin EI 60 | krohv 2 mm, krohv 10 mm, Kergplokk 76 mm, krohv 10 mm, krohv 2 mm | New
SS2 | 5KORRUS | KERGPLOKKSEIN EI60 | krohv 2 mm, krohv 10 mm, Kergplokk 76 mm, krohv 10 mm, krohv 2 mm | New
SS1 | 5KORRUS | Kergplokksin EI 60 | krohv 2 mm, krohv 10 mm, Kergplokk 76 mm, krohv 10 mm, krohv 2 mm | New
3 x SS2 | 5KORRUS | Kergplokksin EI 60 | IFC Building Material 100 mm | New
SS1 | 5KORRUS | KIPSPLAATSEIN | krohv 2 mm, krohv 10 mm, Kergplokk 76 mm, krohv 10 mm, krohv 2 mm | New
2 x SS2 | 5KORRUS | Kergplokksein EI 60 | krohv 2 mm, krohv 10 mm, Kergplokk 76 mm, krohv 10 mm, krohv 2 mm | New
SW - 027 | 5KORRUS |  | krohv 2 mm, krohv 10 mm, Kergplokk 76 mm, krohv 10 mm, krohv 2 mm | New

# IfcWallStandardCase: Olemasolevad seinad tellis, uus viimistlus 200 (6)
Material: Olemasolevad seinad tellis, uus viimistlus 200 mm
Name | In | Description | Renovation Status
2 x KS1 | 1KORRUS | OLEV TELLISSEIN | Existing
ks1 | 2KORRUS | olev kandesein | Existing
KS1 | 3KORRUS | OLEV TELLISSEIN | New
KS1 | 4KORRUS | OLEV Tellissein | New
KS1 | 5KORRUS | olev tellis, viimistlus | New

# IfcWallStandardCase: Olemasolevad seinad tellis, uus viimistlus 300 (105)
Material: Olemasolevad seinad tellis, uus viimistlus 300 mm
Name | In | Description | Renovation Status
VS1 | Sokkel | OLEV TELLISSEIN, L ISASOOJUSTUS, FASSAADIKATE | Existing
2 x KS1 | 1KORRUS | OLEV TELLISSEIN | Existing
2 x VS1 | 1KORRUS | OLEV TELLISSEIN | Existing
KS1 | 1KORRUS | OLEV TELLISSEIN | New
VS1 | 1KORRUS | OLEV TELLISSEIN, L ISASOOJUSTUS, FASSAADIKATE | Existing
7 x ks1 | 2KORRUS | olev kandesein | Existing
2 x VS1 | 2KORRUS | OLEV TELLISSEIN, LISASOOJUSTUS, FASSAADIKATE | Existing
25 x KS1 | 3KORRUS | OLEV TELLISSEIN | Existing
VS1 | 3KORRUS | OLEV TELLISKIVISEIN, LISASOOJUSTUS, FASSAADIKATTEPLAAT TEMPSI | Existing
2 x SS2 | 3KORRUS | OLEV TELLISSEIN | New
2 x KS1 | 3KORRUS | OLEV TELLISSEIN | New
2 x VS1 | 3KORRUS | OLEV TELLISSEIN | Existing
VS1 | 4KORRUS | OLEV TELLISKIVISEIN, LISASOOJUSTUS, FASSAADIKATTEPLAAT TEMPSI | Existing
5 x KS1 | 4KORRUS | OLEV Tellissein | New
22 x KS1 | 4KORRUS | OLEV Tellissein | Existing
22 x KS1 | 5KORRUS | olev tellis, viimistlus | Existing
2 x VS1 | 5KORRUS | Olemasolev välissein.Lisasoojustus kivivill, fassaadikatteplaat Tempsi | Existing
5 x KS1 | 5KORRUS | olev tellis, viimistlus | New

# IfcWallStandardCase: Olemasolevad seinad tellis, uus viimistlus 400 (86)
Material: Olemasolevad seinad tellis, uus viimistlus 400 mm
Name | In | Renovation Status | Description
21 x VS1 | Sokkel | Existing
5 x SS1 | Sokkel | Existing
VS1 | Sokkel | Existing | TELLISSEIN, L ISASOOJUSTUS, FASSAADIKATE
VS1 | Sokkel | New
VS1 | 1KORRUS | New | OLEV TELLISSEIN, L ISASOOJUSTUS, FASSAADIKATE
9 x VS1 | 1KORRUS | Existing | OLEV TELLISSEIN, L ISASOOJUSTUS, FASSAADIKATE
VS1 | 1KORRUS | Existing | OLEV TELLISSEIN
9 x vs1 | 2KORRUS | Existing | olev välissein
ks1 | 2KORRUS | Existing | olev kandesein
VS1 | 2KORRUS | Existing | OLEV VÄLISSEIN
5 x VS1 | 3KORRUS | Existing | OLEV TELLISSEIN, LISASOOJUSTUS, FASSAADIKATE
4 x VS1 | 3KORRUS | Existing | OLEV TELLISKIVISEIN, LISASOOJUSTUS, FASSAADIKATTEPLAAT TEMPSI
VS1 | 3KORRUS | New | OLEV TELLISSEIN
VS1 | 3KORRUS | New | OLEV TELLISKIVISEIN, LISASOOJUSTUS, FASSAADIKATTEPLAAT TEMPSI
11 x VS1 | 4KORRUS | Existing | OLEV TELLISKIVISEIN, LISASOOJUSTUS, FASSAADIKATTEPLAAT TEMPSI
2 x VS1 | 4KORRUS | New | OLEV TELLISKIVISEIN, LISASOOJUSTUS, FASSAADIKATTEPLAAT TEMPSI
10 x VS1 | 5KORRUS | Existing | Olemasolev välissein.Lisasoojustus kivivill, fassaadikatteplaat Tempsi
2 x VS1 | 5KORRUS | New | Olemasolev välissein.Lisasoojustus kivivill, fassaadikatteplaat Tempsi

# IfcWallStandardCase: Olemasolevad seinad tellis, uus viimistlus 500 (126)
Material: Olemasolevad seinad tellis, uus viimistlus 500 mm
Name | In | Description | Renovation Status
VS1 | Sokkel | OLEV TELLISSEIN, L ISASOOJUSTUS, FASSAADIKATE | New
26 x VS1 | 1KORRUS | OLEV TELLISSEIN, L ISASOOJUSTUS, FASSAADIKATE | Existing
2 x VS1 | 1KORRUS | OLEV TELLISSEIN, L ISASOOJUSTUS, FASSAADIKATE | New
16 x vs1 | 2KORRUS | olev välissein | Existing
6 x VS1 | 2KORRUS | OLEV VÄLISSEIN | Existing
VS1 | 2KORRUS | OLEV TELLISSEIN, LISASOOJUSTUS, FASSAADIKATE | Existing
11 x VS1 | 3KORRUS | OLEV TELLISSEIN, LISASOOJUSTUS, FASSAADIKATE | Existing
11 x VS1 | 3KORRUS | OLEV TELLISKIVISEIN, LISASOOJUSTUS, FASSAADIKATTEPLAAT TEMPSI | Existing
VS1 | 3KORRUS | OLEV TELLISKIVISEIN, LISASOOJUSTUS, FASSAADIKATTEPLAAT TEMPSI | New
2 x VS1 | 3KORRUS | OLEV TELLISSEIN, LISASOOJUSTUS, FASSAADIKATE | New
3 x VS1 | 4KORRUS | OLEV TELLISKIVISEIN, LISASOOJUSTUS, FASSAADIKATTEPLAAT TEMPSI | New
22 x VS1 | 4KORRUS | OLEV TELLISKIVISEIN, LISASOOJUSTUS, FASSAADIKATTEPLAAT TEMPSI | Existing
22 x VS1 | 5KORRUS | Olemasolev välissein.Lisasoojustus kivivill, fassaadikatteplaat Tempsi | Existing
2 x VS1 | 5KORRUS | Olemasolev välissein.Lisasoojustus kivivill, fassaadikatteplaat Tempsi | New

# IfcWallStandardCase: Plekkkattega soojustatud paneel 125 (14)
Description: Soojustatud sisesein PIR PANEEL; Material: Teras 12.5 mm, Kõva mineraalvill 100 mm, Teras 12.5 mm
AC_Pset_RenovationAndPhasing - Renovation Status: New
Name | In
6 x SS3 | 3KORRUS
4 x SS3 | 4KORRUS
4 x SS3 | 5KORRUS

# IfcWallStandardCase: Terasprofiil 60 (25)
Description: TERASKARKASSEIN EI60; Material: Terasprofiil 60 mm
Name | In | Renovation Status
2 x Lifti sein | 1KORRUS | New
3 x LS1 | 1KORRUS | New
2 x Lifti sein | 2KORRUS | New
3 x LS1 | 2KORRUS | New
Lifti sein | 3KORRUS | Existing
3 x LS1 | 3KORRUS | New
Lifti sein | 3KORRUS | New
5 x Lifti sein | 4KORRUS | New
LS1 | 5KORRUS | Existing
3 x LS1 | 5KORRUS | New
Lifti sein | 5KORRUS | New

# IfcWallStandardCase: VS2 Uus välissein kergplokk, soojustus, plaat 400 (4)
In: 1KORRUS
Description: KERGPLOKKSEIN, SOOJUSTUS, FASSAADIKATTEPLAAT
AC_Pset_RenovationAndPhasing - Renovation Status: New
Name | Material
2 x VS2 | Kergplokk 200 mm, Plaat 200 mm
2 x VS2 | Plaat 200 mm, Kergplokk 200 mm

# IfcWallStandardCase: kipssein150 150 (416)
AC_Pset_RenovationAndPhasing - Renovation Status: New
Name | In | Description | Material
SS1 | 1KORRUS | KIPSPLAATSEIN | UmbKipsplaat 13 mm, UmbKipsplaat 13 mm, SOOJUSTUS MINERAALVILL 98 mm, UmbKipsplaat 13 mm, UmbKipsplaat 13 mm
134 x SS1 | 3KORRUS | Rajatav kipsplaat | UmbKipsplaat 13 mm, UmbKipsplaat 13 mm, SOOJUSTUS MINERAALVILL 98 mm, UmbKipsplaat 13 mm, UmbKipsplaat 13 mm
4 x SS1 | 3KORRUS | Rajatav2x kipsplaat tulekindel | UmbKipsplaat 13 mm, UmbKipsplaat 13 mm, SOOJUSTUS MINERAALVILL 98 mm, UmbKipsplaat 13 mm, UmbKipsplaat 13 mm
2 x SS1 | 3KORRUS | Kipsplaatvahesein | UmbKipsplaat 13 mm, UmbKipsplaat 13 mm, SOOJUSTUS MINERAALVILL 98 mm, UmbKipsplaat 13 mm, UmbKipsplaat 13 mm
141 x SS1 | 4KORRUS | Kipsplaatvahesein | UmbKipsplaat 13 mm, UmbKipsplaat 13 mm, SOOJUSTUS MINERAALVILL 98 mm, UmbKipsplaat 13 mm, UmbKipsplaat 13 mm
127 x SS1 | 5KORRUS | KIPSPLAATSEIN | UmbKipsplaat 13 mm, UmbKipsplaat 13 mm, SOOJUSTUS MINERAALVILL 98 mm, UmbKipsplaat 13 mm, UmbKipsplaat 13 mm
7 x SS1 | 5KORRUS | KIPSPLAATSEIN | IFC Building Material 150 mm

# IfcWindow: Double Window 19, Olemasolevad aknad jäävad
In: 1KORRUS
Type - OperationType: DOUBLE_PANEL_VERTICAL; ParameterTakesPrecedence: no; Sizeable: no
Type - Window Lining Properties - LiningDepth: 50 mm; LiningThickness: 50 mm; MullionThickness: 50 mm; FirstMullionOffset: 0.285714
Type - Window Panel Properties - Panel 1 - OperationType: SIDEHUNGLEFTHAND; PanelPosition: RIGHT; FrameDepth: 50 mm; FrameThickness: 50 mm
Type - Window Panel Properties - Panel 2 - OperationType: SIDEHUNGRIGHTHAND; PanelPosition: LEFT; FrameDepth: 50 mm; FrameThickness: 50 mm
Description: PLASTPROFIIL AKEN; OverallHeight: 1200 mm; OverallWidth: 2800 mm; Material: Background
AC_Pset_RenovationAndPhasing - Renovation Status: Existing

# IfcWindow: Double Window 19, Olemasolevad aknad jäävad
In: 1KORRUS
Type - OperationType: DOUBLE_PANEL_VERTICAL; ParameterTakesPrecedence: no; Sizeable: no
Type - Window Lining Properties - LiningDepth: 50 mm; LiningThickness: 50 mm; MullionThickness: 50 mm; FirstMullionOffset: 0.290527
Type - Window Panel Properties - Panel 1 - OperationType: SIDEHUNGLEFTHAND; PanelPosition: RIGHT; FrameDepth: 50 mm; FrameThickness: 50 mm
Type - Window Panel Properties - Panel 2 - OperationType: SIDEHUNGRIGHTHAND; PanelPosition: LEFT; FrameDepth: 50 mm; FrameThickness: 50 mm
Description: PLASTPROFIIL AKEN; OverallHeight: 1200 mm; OverallWidth: 2753.62 mm; Material: Background
AC_Pset_RenovationAndPhasing - Renovation Status: Existing

# IfcWindow: Double Window 19 (27)
Type - OperationType: DOUBLE_PANEL_VERTICAL; ParameterTakesPrecedence: no; Sizeable: no
Type - Window Lining Properties - LiningDepth: 50 mm; LiningThickness: 50 mm; MullionThickness: 50 mm; FirstMullionOffset: 0.290909
Type - Window Panel Properties - Panel 1 - OperationType: SIDEHUNGLEFTHAND; PanelPosition: RIGHT; FrameDepth: 50 mm; FrameThickness: 50 mm
Type - Window Panel Properties - Panel 2 - OperationType: SIDEHUNGRIGHTHAND; PanelPosition: LEFT; FrameDepth: 50 mm; FrameThickness: 50 mm
Description: PLASTPROFIIL AKEN; OverallHeight: 1200 mm; OverallWidth: 2750 mm; Material: Background
AC_Pset_RenovationAndPhasing - Renovation Status: Existing
Name | In
9 x Olemasolevad aknad jäävad | 1KORRUS
18 x A1 | 2KORRUS

# IfcWindow: Double Window 19, Olemasolevad aknad jäävad
In: 1KORRUS
Type - OperationType: DOUBLE_PANEL_VERTICAL; ParameterTakesPrecedence: no; Sizeable: no
Type - Window Lining Properties - LiningDepth: 50 mm; LiningThickness: 50 mm; MullionThickness: 50 mm; FirstMullionOffset: 0.29162
Type - Window Panel Properties - Panel 1 - OperationType: SIDEHUNGLEFTHAND; PanelPosition: RIGHT; FrameDepth: 50 mm; FrameThickness: 50 mm
Type - Window Panel Properties - Panel 2 - OperationType: SIDEHUNGRIGHTHAND; PanelPosition: LEFT; FrameDepth: 50 mm; FrameThickness: 50 mm
Description: PLASTPROFIIL AKEN; OverallHeight: 1200 mm; OverallWidth: 2743.29 mm; Material: Background
AC_Pset_RenovationAndPhasing - Renovation Status: Existing

# IfcWindow: Double Window 19, A1
In: 2KORRUS
Type - OperationType: DOUBLE_PANEL_VERTICAL; ParameterTakesPrecedence: no; Sizeable: no
Type - Window Lining Properties - LiningDepth: 50 mm; LiningThickness: 50 mm; MullionThickness: 50 mm; FirstMullionOffset: 0.291768
Type - Window Panel Properties - Panel 1 - OperationType: SIDEHUNGLEFTHAND; PanelPosition: RIGHT; FrameDepth: 50 mm; FrameThickness: 50 mm
Type - Window Panel Properties - Panel 2 - OperationType: SIDEHUNGRIGHTHAND; PanelPosition: LEFT; FrameDepth: 50 mm; FrameThickness: 50 mm
Description: PLASTPROFIIL AKEN; OverallHeight: 1200 mm; OverallWidth: 2741.91 mm; Material: Background
AC_Pset_RenovationAndPhasing - Renovation Status: Existing

# IfcWindow: Double Window 19, A1
In: 2KORRUS
Type - OperationType: DOUBLE_PANEL_VERTICAL; ParameterTakesPrecedence: no; Sizeable: no
Type - Window Lining Properties - LiningDepth: 50 mm; LiningThickness: 50 mm; MullionThickness: 50 mm; FirstMullionOffset: 0.292138
Type - Window Panel Properties - Panel 1 - OperationType: SIDEHUNGLEFTHAND; PanelPosition: RIGHT; FrameDepth: 50 mm; FrameThickness: 50 mm
Type - Window Panel Properties - Panel 2 - OperationType: SIDEHUNGRIGHTHAND; PanelPosition: LEFT; FrameDepth: 50 mm; FrameThickness: 50 mm
Description: PLASTPROFIIL AKEN; OverallHeight: 1200 mm; OverallWidth: 2738.43 mm; Material: Background
AC_Pset_RenovationAndPhasing - Renovation Status: Existing

# IfcWindow: Double Window 19, A1
In: 2KORRUS
Type - OperationType: DOUBLE_PANEL_VERTICAL; ParameterTakesPrecedence: no; Sizeable: no
Type - Window Lining Properties - LiningDepth: 50 mm; LiningThickness: 50 mm; MullionThickness: 50 mm; FirstMullionOffset: 0.297047
Type - Window Panel Properties - Panel 1 - OperationType: SIDEHUNGLEFTHAND; PanelPosition: RIGHT; FrameDepth: 50 mm; FrameThickness: 50 mm
Type - Window Panel Properties - Panel 2 - OperationType: SIDEHUNGRIGHTHAND; PanelPosition: LEFT; FrameDepth: 50 mm; FrameThickness: 50 mm
Description: PLASTPROFIIL AKEN; OverallHeight: 1200 mm; OverallWidth: 2693.17 mm; Material: Background
AC_Pset_RenovationAndPhasing - Renovation Status: Existing

# IfcWindow: Double Window 19 (68)
Type - OperationType: DOUBLE_PANEL_VERTICAL; ParameterTakesPrecedence: no; Sizeable: no
Type - Window Lining Properties - LiningDepth: 50 mm; LiningThickness: 50 mm; MullionThickness: 50 mm; FirstMullionOffset: 0.333333
Type - Window Panel Properties - Panel 1 - OperationType: SIDEHUNGLEFTHAND; PanelPosition: RIGHT; FrameDepth: 50 mm; FrameThickness: 50 mm
Type - Window Panel Properties - Panel 2 - OperationType: SIDEHUNGRIGHTHAND; PanelPosition: LEFT; FrameDepth: 50 mm; FrameThickness: 50 mm
Description: PLASTPROFIIL AKEN; OverallHeight: 1200 mm; OverallWidth: 2400 mm; Material: Background
Name | In | Renovation Status
Olemasolevad aknad jäävad | 1KORRUS | Existing
21 x A1 | 3KORRUS | New
23 x A1 | 4KORRUS | New
23 x A1 | 5KORRUS | New

# IfcWindow: Double Window 19, Olemasolevad aknad jäävad
In: 1KORRUS
Type - OperationType: DOUBLE_PANEL_VERTICAL; ParameterTakesPrecedence: no; Sizeable: no
Type - Window Lining Properties - LiningDepth: 50 mm; LiningThickness: 50 mm; MullionThickness: 50 mm; FirstMullionOffset: 0.377943
Type - Window Panel Properties - Panel 1 - OperationType: SIDEHUNGLEFTHAND; PanelPosition: RIGHT; FrameDepth: 50 mm; FrameThickness: 50 mm
Type - Window Panel Properties - Panel 2 - OperationType: SIDEHUNGRIGHTHAND; PanelPosition: LEFT; FrameDepth: 50 mm; FrameThickness: 50 mm
Description: PLASTPROFIIL AKEN; OverallHeight: 1200 mm; OverallWidth: 2116.72 mm; Material: Background
AC_Pset_RenovationAndPhasing - Renovation Status: Existing

# IfcWindow: Double Window 19, Olemasolevad aknad jäävad
In: 1KORRUS
Type - OperationType: DOUBLE_PANEL_VERTICAL; ParameterTakesPrecedence: no; Sizeable: no
Type - Window Lining Properties - LiningDepth: 50 mm; LiningThickness: 50 mm; MullionThickness: 50 mm; FirstMullionOffset: 0.504601
Type - Window Panel Properties - Panel 1 - OperationType: SIDEHUNGLEFTHAND; PanelPosition: RIGHT; FrameDepth: 50 mm; FrameThickness: 50 mm
Type - Window Panel Properties - Panel 2 - OperationType: SIDEHUNGRIGHTHAND; PanelPosition: LEFT; FrameDepth: 50 mm; FrameThickness: 50 mm
Description: PLASTPROFIIL AKEN; OverallHeight: 1200 mm; OverallWidth: 1585.41 mm; Material: Background
AC_Pset_RenovationAndPhasing - Renovation Status: Existing

# IfcWindow: Double Window 19 (67)
Type - OperationType: DOUBLE_PANEL_VERTICAL; ParameterTakesPrecedence: no; Sizeable: no
Type - Window Lining Properties - LiningDepth: 50 mm; LiningThickness: 50 mm; MullionThickness: 50 mm; FirstMullionOffset: 0.666667
Type - Window Panel Properties - Panel 1 - OperationType: SIDEHUNGRIGHTHAND; PanelPosition: LEFT; FrameDepth: 50 mm; FrameThickness: 50 mm
Type - Window Panel Properties - Panel 2 - OperationType: SIDEHUNGLEFTHAND; PanelPosition: RIGHT; FrameDepth: 50 mm; FrameThickness: 50 mm
OverallHeight: 1200 mm; OverallWidth: 2400 mm; Material: Background
Name | In | Description | Renovation Status
A2 | Sokkel | PLASTPROFIIL AKEN OSALISELT AVATAV | New
A2 | 1KORRUS | PLASTPROFIIL AKEN OSALISELT AVATAV | New
A2 | 2KORRUS | PLASTPROFIIL AKEN | Existing
21 x A2 | 3KORRUS | PLASTPROFIIL AKEN | New
22 x A2 | 4KORRUS | PLASTPROFIIL AKEN | New
21 x A2 | 5KORRUS | PLASTPROFIIL AKEN | New

# IfcWindow: Double Window 19, Olemasolevad aknad jäävad
In: 1KORRUS
Type - OperationType: DOUBLE_PANEL_VERTICAL; ParameterTakesPrecedence: no; Sizeable: no
Type - Window Lining Properties - LiningDepth: 50 mm; LiningThickness: 50 mm; MullionThickness: 50 mm; FirstMullionOffset: 0.707558
Type - Window Panel Properties - Panel 1 - OperationType: SIDEHUNGRIGHTHAND; PanelPosition: LEFT; FrameDepth: 50 mm; FrameThickness: 50 mm
Type - Window Panel Properties - Panel 2 - OperationType: SIDEHUNGLEFTHAND; PanelPosition: RIGHT; FrameDepth: 50 mm; FrameThickness: 50 mm
Description: PLASTPROFIIL AKEN; OverallHeight: 1200 mm; OverallWidth: 2735.58 mm; Material: Background
AC_Pset_RenovationAndPhasing - Renovation Status: Existing

# IfcWindow: Double Window 19 (28)
Type - OperationType: DOUBLE_PANEL_VERTICAL; ParameterTakesPrecedence: no; Sizeable: no
Type - Window Lining Properties - LiningDepth: 50 mm; LiningThickness: 50 mm; MullionThickness: 50 mm; FirstMullionOffset: 0.709091
Type - Window Panel Properties - Panel 1 - OperationType: SIDEHUNGRIGHTHAND; PanelPosition: LEFT; FrameDepth: 50 mm; FrameThickness: 50 mm
Type - Window Panel Properties - Panel 2 - OperationType: SIDEHUNGLEFTHAND; PanelPosition: RIGHT; FrameDepth: 50 mm; FrameThickness: 50 mm
Description: PLASTPROFIIL AKEN; OverallHeight: 1200 mm; OverallWidth: 2750 mm; Material: Background
AC_Pset_RenovationAndPhasing - Renovation Status: Existing
Name | In
9 x Olemasolevad aknad jäävad | 1KORRUS
19 x A2 | 2KORRUS

# IfcWindow: Vertical Multi-Sash Window 19 (10)
Type - OperationType: USERDEFINED; ParameterTakesPrecedence: no; Sizeable: no
Description: Teras, klaas; OverallHeight: 3100 mm; Material: Background
AC_Pset_RenovationAndPhasing - Renovation Status: New
Name | In | OverallWidth (mm)
Lifti klaassein | 1KORRUS | 900
Lifti klaassein | 1KORRUS | 1280
Lifti klaassein | 2KORRUS | 1280
Lifti klaassein | 2KORRUS | 900
Lifti klaassein | 3KORRUS | 1280
Lifti klaassein | 3KORRUS | 900
Lifti klaassein | 4KORRUS | 1280
Lifti klaassein | 4KORRUS | 900
Lifti klaassein | 5KORRUS | 900
Lifti klaassein | 5KORRUS | 1280

# IfcWindow: Window 19 (8)
Type - OperationType: SINGLE_PANEL; ParameterTakesPrecedence: no; Sizeable: no
Type - Window Lining Properties - LiningDepth: 50 mm; LiningThickness: 50 mm
Type - Window Panel Properties - Panel 1 - OperationType: BOTTOMHUNG; PanelPosition: MIDDLE; FrameDepth: 50 mm; FrameThickness: 50 mm
Material: Background
Name | In | Description | OverallHeight (mm) | OverallWidth (mm) | Renovation Status
Olemasolevad aknad jäävad | 1KORRUS | PLASTPROFIIL AKEN | 1200 | 2281.61 | Existing
A5 | 2KORRUS | PLASTPROFIILIS AKEN | 1100 | 1800 | Existing
A5 | 3KORRUS | PLASTPROFIILIS AKEN | 1100 | 1800 | New
A3 | 3KORRUS | PLASTPROFIIL AKEN | 1200 | 1200 | New
A5 | 4KORRUS | PLASTPROFIILIS AKEN | 1100 | 1800 | New
A3 | 4KORRUS | PLASTPROFIIL AKEN | 1200 | 1200 | New
A3 | 5KORRUS | PLASTPROFIIL AKEN | 1200 | 1200 | New
A5 | 5KORRUS | PLASTPROFIILIS AKEN | 1100 | 1800 | New

# IfcWindow: Window 19 (8)
Type - OperationType: SINGLE_PANEL; ParameterTakesPrecedence: no; Sizeable: no
Type - Window Lining Properties - LiningDepth: 50 mm; LiningThickness: 50 mm
Type - Window Panel Properties - Panel 1 - OperationType: SIDEHUNGLEFTHAND; PanelPosition: MIDDLE; FrameDepth: 50 mm; FrameThickness: 50 mm
Material: Background
Name | In | OverallHeight (mm) | OverallWidth (mm) | Renovation Status
3 x KLA1 | 1KORRUS | 2800 | 1800 | New | Description: FASSAADISÜSTEEM ALUMIINIUM
SA1 | 1KORRUS | 1500 | 2500 | New
WD - 003 | 2KORRUS | 1200 | 1916.4 | Existing
WD - 003 | 2KORRUS | 1200 | 800 | Existing
WD - 003 | 2KORRUS | 1200 | 1200 | Existing
WD - 003 | 2KORRUS | 1200 | 778.367 | Existing

# IfcWindow: Window 19 (10)
In: 1KORRUS
Type - OperationType: SINGLE_PANEL; ParameterTakesPrecedence: no; Sizeable: no
Type - Window Lining Properties - LiningDepth: 50 mm; LiningThickness: 50 mm
Type - Window Panel Properties - Panel 1 - OperationType: SIDEHUNGRIGHTHAND; PanelPosition: MIDDLE; FrameDepth: 50 mm; FrameThickness: 50 mm
Material: Background
Name | OverallHeight (mm) | OverallWidth (mm) | Renovation Status
Olemasolevad aknad jäävad | 1000 | 2565.88 | Existing
Olemasolevad aknad jäävad | 1000 | 992.491 | Existing
Olemasolevad aknad jäävad | 1000 | 804.797 | Existing
4 x Olemasolevad aknad jäävad | 1600 | 2281.3 | Existing
Olemasolevad aknad jäävad | 1600 | 5501.5 | Existing
Olemasolevad aknad jäävad | 1600 | 4225.17 | Existing
A6 | 2800 | 1000 | New | Description: PLASTPROFIIL AKEN
